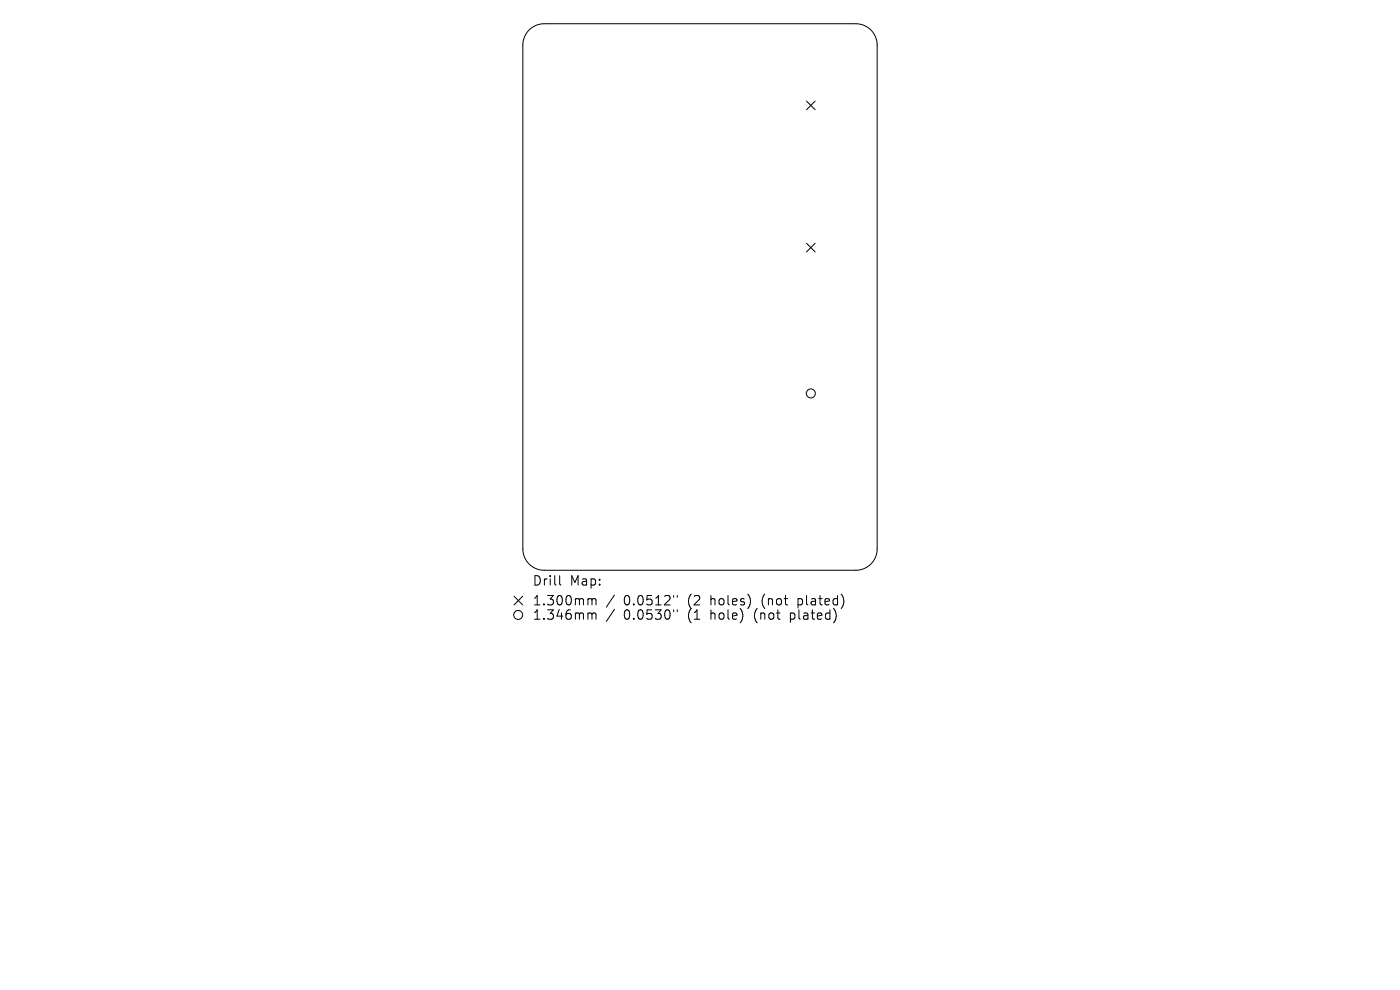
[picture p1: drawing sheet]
<svg xmlns="http://www.w3.org/2000/svg" width="297mm" height="210mm" viewBox="0 0 297 210" stroke-linecap="round" stroke-linejoin="round" font-family="sans-serif">
<defs><g id="words">
<g font-size="2.8">
<text x="112.9" y="124.5">Drill</text>
<text x="120.9" y="124.5">Map:</text>
<text x="112.9" y="128.7">1.300mm</text>
<text x="112.9" y="131.7">1.346mm</text>
<text x="132.3" y="128.7">0.0512&quot;</text>
<text x="132.3" y="131.7">0.0530&quot;</text>
<text x="146.1" y="128.7">(2</text>
<text x="146.1" y="131.7">(1</text>
<text x="151" y="128.7">holes)</text>
<text x="151" y="131.7">hole)</text>
<text x="160.5" y="131.7">(not</text>
<text x="162.1" y="128.7">(not</text>
<text x="168.3" y="131.7">plated)</text>
<text x="169.9" y="128.7">plated)</text>
</g>
</g></defs>
<g fill="none" stroke="#000" stroke-width=".21">
<path d="M112.2 6.4a4.5 4.5 0 0 1 3.2-1.4h66.2a4.5 4.5 0 0 1 4.5 4.6v106.8a4.5 4.5 0 0 1-4.5 4.6h-66.2a4.5 4.5 0 0 1-4.5-4.6v-106.8a4.5 4.5 0 0 1 1.3-3.2zM171.1 21.4l1.8 1.9M172.9 21.4l-1.8 1.9M171.1 51.6l1.8 1.8M172.9 51.6l-1.8 1.8M109 126.5l1.9 1.8M110.9 126.5l-1.9 1.8M118.7 122.1v1.7l.3 .3M125 127h.3l.3 .3M125 130l.5 .1 .1 .2M125.6 127.3l.3-.3 .4 .1 .1 1.2M125.6 127.3v1"/>
<path d="M125.6 130.3v1.1M125.6 130.3l.3-.3 .4 .1 .1 1.3M130.3 126.2l-1.7 2.6M130.3 129.3l-1.7 2.5M142.9 126.3v.4M142.9 129.4v.3M143.7 126.3v.4M143.7 129.4v.3"/>
<circle cx="172" cy="83.5" r=".95"/>
<circle cx="109.9" cy="130.4" r=".95"/>
</g>
<use href="#words"/>
</svg>
